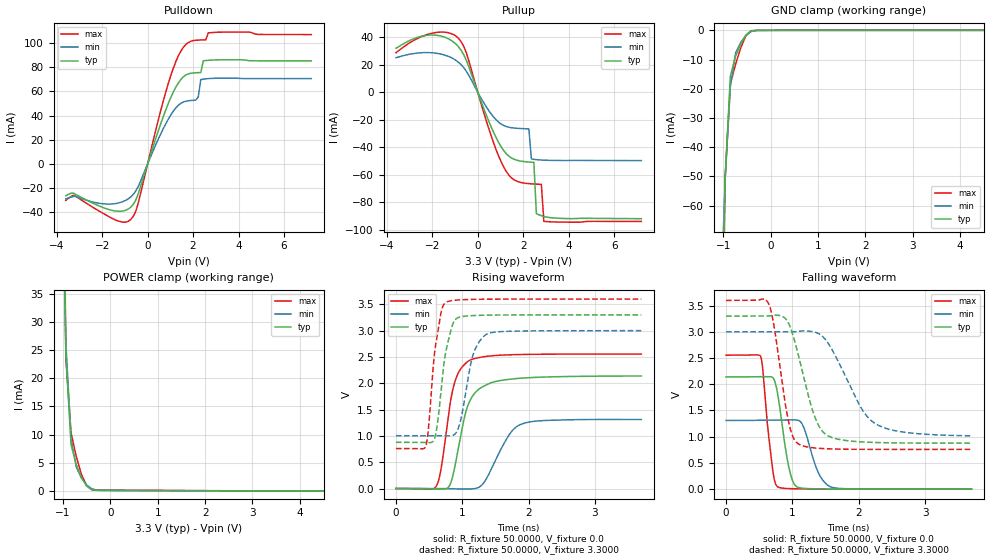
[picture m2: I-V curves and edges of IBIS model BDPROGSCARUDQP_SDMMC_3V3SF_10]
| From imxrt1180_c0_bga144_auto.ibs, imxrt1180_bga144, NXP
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[Model]  BDPROGSCARUDQP_SDMMC_3V3SF_10
|   Model BDPROGSCARUDQP_SDMMC_3V3SF_10
| This model was characterised for following simulation conditions:
| External (pad) voltage:
|   - Typ: 3.3V,   - Min: 3.0V,   - Max: 3.6V
| Library cells for typ/min/max conditions are connected as defined below:
|  IO - External Pad
|  A - Core Input
|  EN - Output Buffer Enable
|  ASRCN3V3[0] - REFH3V3 gnde REFH3V3
|  ASRCN3V3[1] - REFH3V3 REFH3V3 gnde
|  ASRCN3V3[2] - gnde
|  ASRCN3V3[3] - gnde REFH3V3 gnde
|  ASRCP3V3[0] - vdde3v3 vdde3v3 REFL3V3
|  ASRCP3V3[1] - vdde3v3 REFL3V3 vdde3v3
|  ASRCP3V3[2] - REFL3V3 vdde3v3 vdde3v3
|  ASRCP3V3[3] - REFL3V3 REFL3V3 vdde3v3
|  IOGC - NC
|  PDRV - gnd
|  PSW - vdd
|  REFH3V3 - REFH3V3
|  REFL3V3 - REFL3V3
|  ZI - NC
|  gnd - gnd
|  gnde - gnde
|  vdd - vdd
|  vdde3v3 - vdde3v3
| All other pins connected to ground
Model_type I/O
Polarity   Non-Inverting
Enable   Active-Low
Vinl =   0.7500V
Vinh =   2.2500V
Vmeas =  1.6500V
Cref =   30.0000pF
Rref =   1.0000M
Vref =   3.3000V
C_comp   2.1236pF   2.1100pF   2.1437pF
|C_comp_pullup   0.3619pF   0.3760pF   0.3515pF
|C_comp_pulldown   0.6265pF   0.6611pF   0.5987pF
[Model Spec]
| variable   typ   min   max
Vinh   2.0625V   1.8750V   2.2500V
Vinl   0.8250V   0.7500V   0.9000V
[Temperature Range]   25.0000   0.1250k   -40.0000
[Voltage Range]   3.3000V   3.0000V   3.6000V
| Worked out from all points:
|   slope of the pulldown table from 0 to 0.495 V, typ, clamps not added: 17.2 ohm
|   slope of the pullup table from 0 to 0.495 V, typ, clamps not added: 23 ohm
|   GND clamp passes 1 mA (typ) near -0.48 V on its own axis
|   POWER clamp passes 1 mA (typ) near -0.51 V on its own axis
|   rising waveform, R_fixture 50.0000, V_fixture 0.0: 20-80 % time 243ps typ, 327ps min, 195ps max; typ from 0 V to 2.14 V
|   rising waveform, R_fixture 50.0000, V_fixture 3.3000: 20-80 % time 152ps typ, 185ps min, 136ps max; typ from 0.878 V to 3.3 V
|   falling waveform, R_fixture 50.0000, V_fixture 0.0: 20-80 % time 153ps typ, 205ps min, 118ps max; typ from 2.14 V to 0 V
|   falling waveform, R_fixture 50.0000, V_fixture 3.3000: 20-80 % time 307ps typ, 487ps min, 203ps max; typ from 3.3 V to 0.877 V
[Pulldown]
|Voltage   I(typ)   I(min)   I(max)
-3.6V     -26.23mA   -28.9mA    -30.08mA
-3.27V    -24.11mA   -26.9mA    -25.84mA
-1.4V     -38.9mA    -32.67mA   -46.39mA
-630mV    -33.34mA   -25.14mA   -43.24mA
1.02V     54.81mA    40.43mA    73.04mA
1.79V     74.36mA    52.16mA    100.3mA
2.23V     75.41mA    55.35mA    102.3mA
2.34V     75.48mA    69.67mA    102.4mA
2.45V     85.15mA    70.02mA    102.4mA
2.56V     85.39mA    70.29mA    102.4mA
2.89V     85.84mA    70.71mA    108.6mA
7.2V      85.14mA    70.48mA    106.8mA
[Pullup]
|Voltage   I(typ)   I(min)   I(max)
-3.6V     31.94mA    25.02mA    28.66mA
-2.04V    41.59mA    28.67mA    42.73mA
-830mV    32.67mA    21.51mA    38.87mA
-500mV    23.13mA    15.19mA    28.53mA
1.15V     -42.62mA   -24.3mA    -54.63mA
2.25V     -50.81mA   -26.67mA   -66.51mA
2.36V     -50.94mA   -48.52mA   -66.66mA
2.47V     -51.06mA   -48.83mA   -66.78mA
2.58V     -88.31mA   -49.06mA   -66.88mA
2.8V      -89.83mA   -49.35mA   -67.05mA
2.91V     -90.37mA   -49.43mA   -93.93mA
7.2V      -91.99mA   -49.74mA   -94.02mA
[GND_clamp]
|Voltage   I(typ)   I(min)   I(max)
-3.6V     -5.131A    -2.875A    -8.762A
-1.07V    -134.2mA   -102.6mA   -176.8mA
-960mV    -50.84mA   -50.99mA   -50.43mA
-850mV    -15.74mA   -19.19mA   -18.44mA
-740mV    -8.808mA   -7.773mA   -11.63mA
-630mV    -4.596mA   -4.129mA   -5.959mA
-520mV    -1.551mA   -1.768mA   -1.8mA
-410mV    -182.3uA   -416.9uA   -135.3uA
-190mV    -16.94uA   -14.45uA   -23.35uA
7.2V      0A         0A         0A
[POWER_clamp]
|Voltage   I(typ)   I(min)   I(max)
-3.6V     5.01A      2.759A     8.682A
-1.05V    90.64mA    70.4mA     118.9mA
-940mV    24.29mA    26.42mA    23.58mA
-830mV    8.246mA    9.229mA    10.3mA
-720mV    4.663mA    4.226mA    6.11mA
-610mV    2.344mA    2.293mA    2.91mA
-500mV    850.8uA    1.048mA    919.3uA
-390mV    222uA      361.4uA    219.3uA
-280mV    111uA      115.7uA    149.6uA
-60mV     99.3uA     71.05uA    139.3uA
7.2V      0A         0A         0A
[Ramp]
| variable   typ   min   max
dV/dt_r  1.2825/0.2428n   0.7868/0.3266n   1.5326/0.1947n
dV/dt_f  1.4529/0.3068n   1.1898/0.4872n   1.7036/0.2030n
R_load = 50.0000
[Rising Waveform]
R_fixture= 50.0000
V_fixture= 0.0
V_fixture_min= 0.0
V_fixture_max= 0.0
|time   V(typ)   V(min)   V(max)
0s        133.3uV    123.5uV    154.7uV
615.6ps   -10.75mV   176.8uV    61.73mV
684.1ps   -9.759mV   -18.26uV   399.9mV
788.8ps   20.78mV    -2.203mV   1.357V
876.4ps   342.6mV    -5.5mV     1.974V
1.11ns    1.654V     -8.638mV   2.435V
1.32ns    1.942V     101.2mV    2.503V
1.705ns   2.074V     1.016V     2.539V
1.89ns    2.096V     1.222V     2.546V
3.7ns     2.138V     1.311V     2.554V
[Rising Waveform]
R_fixture= 50.0000
V_fixture= 3.3000
V_fixture_min= 3.0000
V_fixture_max= 3.6000
|time   V(typ)   V(min)   V(max)
0s        877.7mV    1.003V     759.5mV
452.6ps   877.1mV    1.003V     814.5mV
492.7ps   872.9mV    1.003V     1.169V
599.5ps   1.03V      1.003V     2.736V
688.2ps   1.969V     1.003V     3.388V
747.4ps   2.563V     1.001V     3.53V
907.5ps   3.223V     1.061V     3.578V
1.158ns   3.284V     2.52V      3.593V
1.362ns   3.292V     2.925V     3.596V
3.7ns     3.299V     2.998V     3.598V
[Falling Waveform]
R_fixture= 50.0000
V_fixture= 0.0
V_fixture_min= 0.0
V_fixture_max= 0.0
|time   V(typ)   V(min)   V(max)
0s        2.139V     1.31V      2.554V
523.8ps   2.144V     1.315V     2.522V
694.7ps   2.135V     1.317V     445.5mV
782.9ps   1.784V     1.318V     41.82mV
938.6ps   466.9mV    1.318V     10.94mV
1.07ns    43.87mV    1.317V     6.162mV
1.173ns   15.61mV    1.175V     4.233mV
1.398ns   5.775mV    297.4mV    1.964mV
1.58ns    3.496mV    42.46mV    1.107mV
3.7ns     140.4uV    282uV      155.1uV
[Falling Waveform]
R_fixture= 50.0000
V_fixture= 3.3000
V_fixture_min= 3.0000
V_fixture_max= 3.6000
|time   V(typ)   V(min)   V(max)
0s        3.299V     2.999V     3.598V
641.4ps   3.302V     2.999V     3.537V
721ps     3.317V     3V         3.127V
940.8ps   3.168V     3V         1.3V
1.091ns   2.548V     3.009V     863.1mV
1.336ns   1.385V     2.994V     785.6mV
1.54ns    1.015V     2.779V     769.5mV
2.038ns   901.2mV    1.548V     759.3mV
2.242ns   890.1mV    1.256V     758.5mV
3.7ns     877.1mV    1.016V     758.8mV
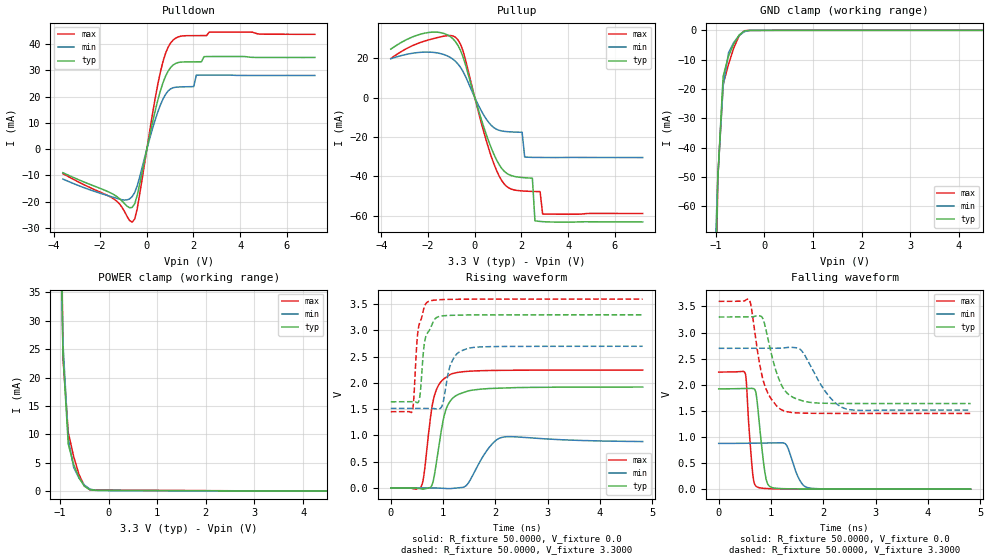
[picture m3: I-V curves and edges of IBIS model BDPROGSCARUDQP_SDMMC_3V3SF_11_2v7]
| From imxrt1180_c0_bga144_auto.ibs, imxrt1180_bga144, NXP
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[Model]  BDPROGSCARUDQP_SDMMC_3V3SF_11_2v7
|   Model BDPROGSCARUDQP_SDMMC_3V3SF_11_2v7
| This model was characterised for following simulation conditions:
| External (pad) voltage:
|   - Typ: 3.3V,   - Min: 2.7V,   - Max: 3.6V
| Library cells for typ/min/max conditions are connected as defined below:
|  IO - External Pad
|  A - Core Input
|  EN - Output Buffer Enable
|  ASRCN3V3[0] - REFH3V3
|  ASRCN3V3[1] - REFH3V3 REFH3V3 gnde
|  ASRCN3V3[2] - gnde REFH3V3 gnde
|  ASRCN3V3[3] - gnde REFH3V3 gnde
|  ASRCP3V3[0] - vdde3v3 REFL3V3 REFL3V3
|  ASRCP3V3[1] - vdde3v3 REFL3V3 vdde3v3
|  ASRCP3V3[2] - REFL3V3 REFL3V3 vdde3v3
|  ASRCP3V3[3] - REFL3V3 REFL3V3 vdde3v3
|  IOGC - NC
|  PDRV - vdd
|  PSW - vdd
|  REFH3V3 - REFH3V3
|  REFL3V3 - REFL3V3
|  ZI - NC
|  gnd - gnd
|  gnde - gnde
|  vdd - vdd
|  vdde3v3 - vdde3v3
| All other pins connected to ground
Model_type I/O
Polarity   Non-Inverting
Enable   Active-Low
Vinl =   0.6750V
Vinh =   2.2500V
Vmeas =  1.6500V
Cref =   30.0000pF
Rref =   1.0000M
Vref =   3.3000V
C_comp   2.1236pF   2.1018pF   2.1437pF
|C_comp_pullup   0.3619pF   0.3778pF   0.3515pF
|C_comp_pulldown   0.6265pF   0.6611pF   0.5987pF
[Model Spec]
| variable   typ   min   max
Vinh   2.0625V   1.6875V   2.2500V
Vinl   0.8250V   0.6750V   0.9000V
[Temperature Range]   25.0000   0.1250k   -40.0000
[Voltage Range]   3.3000V   2.7000V   3.6000V
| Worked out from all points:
|   slope of the pulldown table from 0 to 0.495 V, typ, clamps not added: 25.5 ohm
|   slope of the pullup table from 0 to 0.495 V, typ, clamps not added: 26.4 ohm
|   GND clamp passes 1 mA (typ) near -0.48 V on its own axis
|   POWER clamp passes 1 mA (typ) near -0.51 V on its own axis
|   rising waveform, R_fixture 50.0000, V_fixture 0.0: 20-80 % time 215ps typ, 301ps min, 187ps max; typ from 0 V to 1.92 V
|   rising waveform, R_fixture 50.0000, V_fixture 3.3000: 20-80 % time 135ps typ, 173ps min, 113ps max; typ from 1.64 V to 3.3 V
|   falling waveform, R_fixture 50.0000, V_fixture 0.0: 20-80 % time 124ps typ, 192ps min, 91.3ps max; typ from 1.92 V to 0 V
|   falling waveform, R_fixture 50.0000, V_fixture 3.3000: 20-80 % time 290ps typ, 430ps min, 253ps max; typ from 3.3 V to 1.64 V
[Pulldown]
|Voltage   I(typ)   I(min)   I(max)
-3.6V     -8.96mA    -11.37mA   -9.312mA
-1.4V     -17.38mA   -18.41mA   -19.05mA
-630mV    -22.15mA   -18.07mA   -27.77mA
-410mV    -17.5mA    -13.89mA   -22.58mA
250mV     10.41mA    8.003mA    13.77mA
580mV     22.14mA    16.76mA    29.29mA
800mV     27.69mA    20.78mA    36.37mA
1.13V     32mA       23.33mA    41.48mA
2.01V     33.18mA    23.76mA    43.13mA
2.12V     33.19mA    28.1mA     43.14mA
2.45V     35.15mA    28.14mA    43.15mA
7.2V      34.85mA    28mA       43.63mA
[Pullup]
|Voltage   I(typ)   I(min)   I(max)
-3.6V     24.55mA    19.66mA    19.79mA
-1.93V    33.06mA    23.03mA    29.4mA
-830mV    28.38mA    18.39mA    30.59mA
-500mV    20.5mA     13.17mA    23.56mA
1.04V     -33.9mA    -16.59mA   -39.66mA
2.03V     -40.55mA   -17.62mA   -47.36mA
2.14V     -40.66mA   -30.17mA   -47.44mA
2.47V     -40.88mA   -30.33mA   -47.6mA
2.58V     -62.51mA   -30.35mA   -47.64mA
2.8V      -62.83mA   -30.38mA   -47.71mA
2.91V     -62.93mA   -30.39mA   -59.07mA
7.2V      -63.09mA   -30.42mA   -58.81mA
[GND_clamp]
|Voltage   I(typ)   I(min)   I(max)
-3.6V     -5.131A    -2.873A    -8.762A
-1.07V    -134.2mA   -102.1mA   -176.8mA
-960mV    -50.84mA   -50.69mA   -50.43mA
-850mV    -15.74mA   -19.08mA   -18.44mA
-740mV    -8.808mA   -7.744mA   -11.63mA
-630mV    -4.596mA   -4.116mA   -5.959mA
-520mV    -1.551mA   -1.763mA   -1.8mA
-410mV    -182.3uA   -415.1uA   -135.3uA
-190mV    -16.94uA   -13.14uA   -23.35uA
7.2V      0A         0A         0A
[POWER_clamp]
|Voltage   I(typ)   I(min)   I(max)
-3.6V     5.01A      2.758A     8.682A
-1.05V    90.64mA    70.14mA    118.9mA
-940mV    24.29mA    26.26mA    23.58mA
-830mV    8.246mA    9.16mA     10.3mA
-720mV    4.663mA    4.194mA    6.11mA
-610mV    2.344mA    2.275mA    2.91mA
-500mV    850.8uA    1.038mA    919.3uA
-390mV    222uA      354.3uA    219.3uA
-280mV    111uA      109.1uA    149.6uA
-60mV     99.3uA     64.48uA    139.3uA
7.2V      0A         0A         0A
[Ramp]
| variable   typ   min   max
dV/dt_r  1.1530/0.2150n   0.5300/0.3005n   1.3463/0.1866n
dV/dt_f  0.9946/0.2895n   0.7099/0.4300n   1.2879/0.2530n
R_load = 50.0000
[Rising Waveform]
R_fixture= 50.0000
V_fixture= 0.0
V_fixture_min= 0.0
V_fixture_max= 0.0
|time   V(typ)   V(min)   V(max)
0s        169.4uV    126.4uV    200.5uV
585.5ps   -18.23mV   176.5uV    33.44mV
644.1ps   -17.76mV   178.9uV    319.7mV
775.8ps   30.64mV    13.35uV    1.464V
869.8ps   467.1mV    -1.343mV   1.864V
1.014ns   1.345V     -9mV       2.076V
1.145ns   1.665V     -12.85mV   2.165V
1.456ns   1.84V      57.76mV    2.22V
2.12ns    1.904V     960.9mV    2.24V
4.82ns    1.922V     883.4mV    2.244V
[Rising Waveform]
R_fixture= 50.0000
V_fixture= 3.3000
V_fixture_min= 2.7000
V_fixture_max= 3.6000
|time   V(typ)   V(min)   V(max)
0s        1.641V     1.515V     1.451V
409.3ps   1.643V     1.515V     1.463V
524.4ps   1.631V     1.515V     3.019V
565.1ps   1.817V     1.515V     3.171V
640.1ps   2.737V     1.516V     3.447V
728ps     2.986V     1.516V     3.554V
967.5ps   3.274V     1.539V     3.588V
1.156ns   3.289V     2.38V      3.593V
1.463ns   3.295V     2.653V     3.596V
4.82ns    3.298V     2.699V     3.598V
[Falling Waveform]
R_fixture= 50.0000
V_fixture= 0.0
V_fixture_min= 0.0
V_fixture_max= 0.0
|time   V(typ)   V(min)   V(max)
0s        1.922V     876.5mV    2.244V
506.4ps   1.929V     879.8mV    2.224V
646.6ps   1.929V     881.5mV    332.5mV
737.1ps   1.666V     882.2mV    40.82mV
891ps     273.5mV    885mV      13.71mV
1.01ns    34.43mV    887.7mV    8.331mV
1.29ns    7.887mV    852.7mV    3.289mV
1.533ns   4.066mV    205.5mV    1.616mV
1.723ns   2.534mV    24.68mV    970uV
4.82ns    169.5uV    166.5uV    200.4uV
[Falling Waveform]
R_fixture= 50.0000
V_fixture= 3.3000
V_fixture_min= 2.7000
V_fixture_max= 3.6000
|time   V(typ)   V(min)   V(max)
0s        3.298V     2.699V     3.598V
585ps     3.301V     2.699V     3.625V
774.9ps   3.323V     2.699V     2.444V
866.3ps   3.207V     2.7V       2.031V
1.062ns   2.38V      2.7V       1.653V
1.226ns   1.949V     2.703V     1.509V
1.565ns   1.705V     2.675V     1.458V
2.073ns   1.644V     1.827V     1.452V
2.408ns   1.641V     1.547V     1.452V
4.82ns    1.641V     1.516V     1.452V
